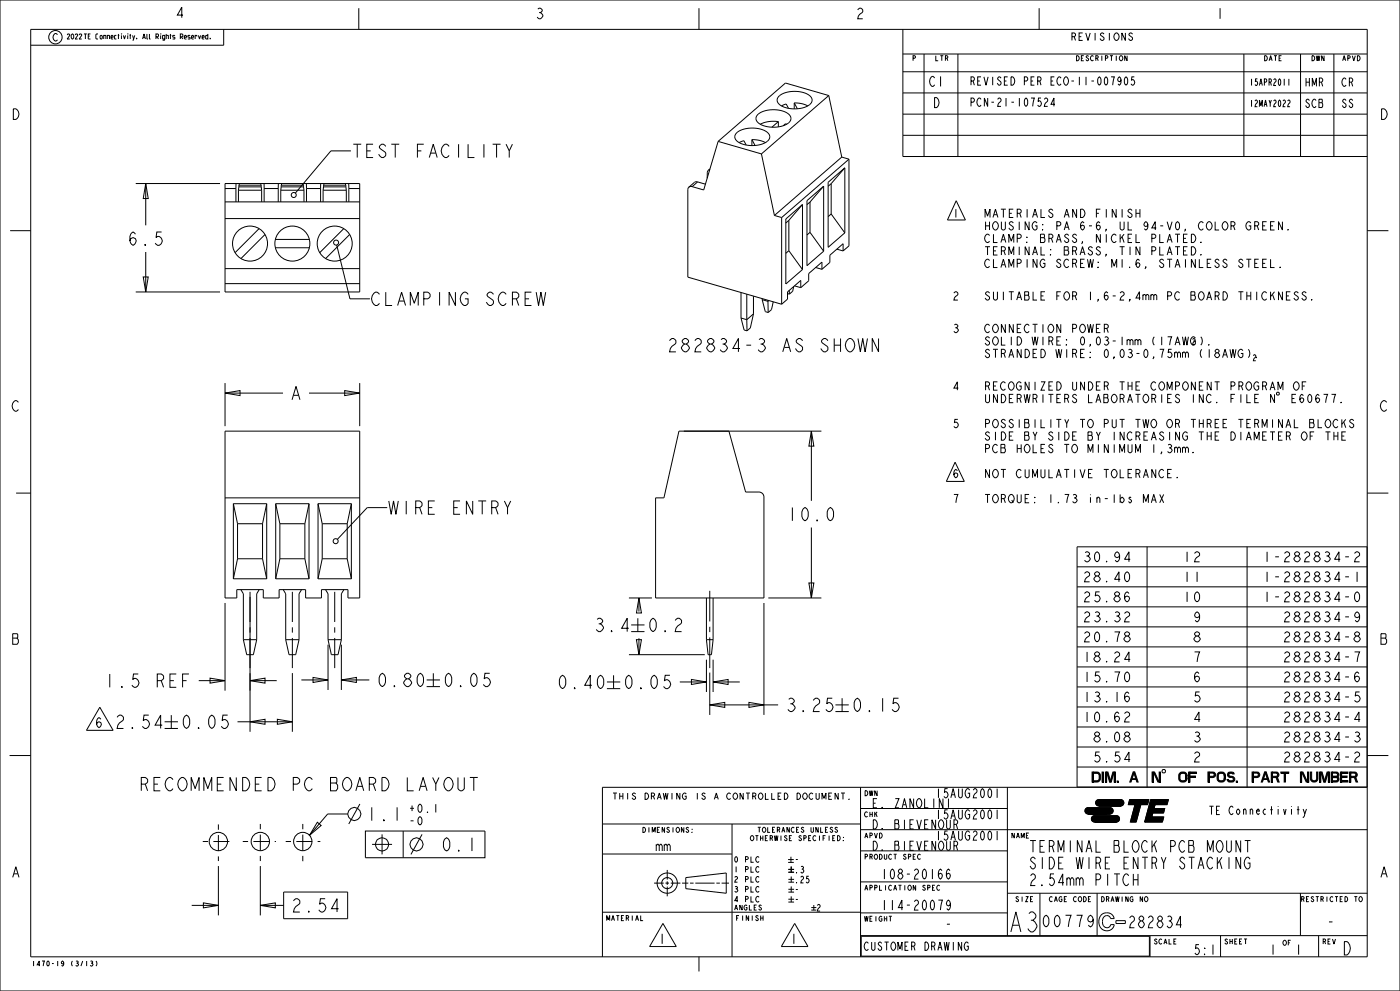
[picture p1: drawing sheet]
<svg xmlns="http://www.w3.org/2000/svg" width="420mm" height="297mm" viewBox="0 0 420 297" stroke-linecap="round" stroke-linejoin="round" font-family="sans-serif">
<defs><g id="words">
<text font-size="7.8" x="302.4" y="279.3">A3</text>
<g font-size="5.2">
<text x="105.3" y="47.2">TEST FACILITY</text>
<text x="38" y="73.5">6.5</text>
<text x="111" y="91.6">CLAMPING SCREW</text>
<text x="205.7" y="105.5">282834-3 AS SHOWN</text>
<text x="86.9" y="119.8">A</text>
<text x="116.2" y="154.1">WIRE ENTRY</text>
<text x="235.8" y="156.1">10.0</text>
<text x="177.9" y="189.3">3.4</text>
<text x="194" y="189.3">0.2</text>
<text x="31" y="206">1.5</text>
<text x="45.5" y="206">REF</text>
<text x="112.8" y="205.8">0.80</text>
<text x="132.7" y="205.8">0.05</text>
<text x="166.9" y="206.4">0.40</text>
<text x="186.7" y="206.4">0.05</text>
<text x="235.4" y="213.3">3.25</text>
<text x="255.3" y="213.3">0.15</text>
<text x="34.2" y="218.3">2.54</text>
<text x="54" y="218.3">0.05</text>
<text x="50.6" y="237">RECOMMENDED PC BOARD LAYOUT</text>
<text x="87.1" y="273.3">2.54</text>
<text x="402.5" y="286.2">D</text>
</g>
<g font-size="4.6">
<text x="308.5" y="255.4">TERMINAL BLOCK PCB MOUNT</text>
<text x="308.5" y="260.4">SIDE WIRE ENTRY STACKING</text>
<text x="308.5" y="265.4">2.54mm PITCH</text>
<text x="312.2" y="277.8">00779</text>
<text x="338.2" y="278">282834</text>
<text x="397.8" y="278">-</text>
</g>
<g font-size="4.1">
<text x="52.5" y="5.3">4</text>
<text x="160.4" y="5.6">3</text>
<text x="256.6" y="5.6">2</text>
<text x="364.5" y="5.6">1</text>
<text x="3.2" y="35.8">D</text>
<text x="413.7" y="35.8">D</text>
<text x="3.2" y="123.2">C</text>
<text x="413.7" y="123.2">C</text>
<text x="3.2" y="193.1">B</text>
<text x="413.7" y="193.1">B</text>
<text x="3.2" y="262.9">A</text>
<text x="413.7" y="262.9">A</text>
</g>
<g font-size="3.9">
<text x="278.6" y="25.9">C1</text>
<text x="279.8" y="32.2">D</text>
<text x="324.6" y="168.4">30.94</text>
<text x="378.1" y="168.4">1-282834-2</text>
<text x="324.6" y="174.4">28.40</text>
<text x="378.1" y="174.4">1-282834-1</text>
<text x="324.6" y="180.4">25.86</text>
<text x="378.1" y="180.4">1-282834-0</text>
<text x="324.6" y="186.4">23.32</text>
<text x="383" y="186.4">282834-9</text>
<text x="324.6" y="192.4">20.78</text>
<text x="383" y="192.4">282834-8</text>
<text x="324.6" y="198.4">18.24</text>
<text x="383" y="198.4">282834-7</text>
<text x="324.6" y="204.4">15.70</text>
<text x="383" y="204.4">282834-6</text>
<text x="324.6" y="210.4">13.16</text>
<text x="383" y="210.4">282834-5</text>
<text x="28.3" y="218.1">6</text>
<text x="324.6" y="216.4">10.62</text>
<text x="383" y="216.4">282834-4</text>
<text x="327.1" y="222.4">8.08</text>
<text x="383" y="222.4">282834-3</text>
<text x="327.1" y="228.4">5.54</text>
<text x="383" y="228.4">282834-2</text>
<text x="327.1" y="234.4">DIM. A</text>
<text x="375.6" y="234.4">PART NUMBER</text>
<text x="196.6" y="255">mm</text>
<text x="264.1" y="263.5">108-20166</text>
<text x="264.1" y="272.8">114-20079</text>
<text x="283.3" y="278.5">-</text>
<text x="197.2" y="282.9">1</text>
<text x="236.7" y="282.9">1</text>
<text x="357.9" y="286.1">5:1</text>
<text x="380.7" y="286.1">1</text>
<text x="388.4" y="286.1">1</text>
</g>
<g font-size="3.6">
<text x="280.4" y="239.1">15AUG2001</text>
<text x="261.4" y="242.1">E. ZANOLINI</text>
<text x="280.4" y="245.5">15AUG2001</text>
<text x="261.4" y="248.4">D. BIEVENOUR</text>
<text x="280.4" y="251.8">15AUG2001</text>
<text x="261.4" y="254.9">D. BIEVENOUR</text>
</g>
<g font-size="3.3">
<text x="290.8" y="25.5">REVISED PER ECO-11-007905</text>
<text x="391.3" y="25.9">HMR</text>
<text x="402.3" y="25.9">CR</text>
<text x="290.8" y="31.9">PCN-21-107524</text>
<text x="391.3" y="32.2">SCB</text>
<text x="402.3" y="32.2">SS</text>
<text x="285.6" y="65.2">1</text>
<text x="293.4" y="65.2">MATERIALS AND FINISH</text>
<text x="293.4" y="68.9">HOUSING: PA 6-6, UL 94-V0, COLOR GREEN.</text>
<text x="293.4" y="72.7">CLAMP: BRASS, NICKEL PLATED.</text>
<text x="293.4" y="76.4">TERMINAL: BRASS, TIN PLATED.</text>
<text x="293.4" y="80.2">CLAMPING SCREW: M1.6, STAINLESS STEEL.</text>
<text x="285.6" y="89.9">2</text>
<text x="293.4" y="89.9">SUITABLE FOR 1,6-2,4mm PC BOARD THICKNESS.</text>
<text x="285.6" y="99.7">3</text>
<text x="293.4" y="99.7">CONNECTION POWER</text>
<text x="293.4" y="103.4">SOLID WIRE: 0,03-1mm (17AWG).</text>
<text x="293.4" y="107.2">STRANDED WIRE: 0,03-0,75mm (18AWG).</text>
<text x="285.6" y="116.9">4</text>
<text x="293.4" y="116.9">RECOGNIZED UNDER THE COMPONENT PROGRAM OF</text>
<text x="285.6" y="128.2">5</text>
<text x="293.4" y="128.2">POSSIBILITY TO PUT TWO OR THREE TERMINAL BLOCKS</text>
<text x="293.4" y="131.9">SIDE BY SIDE BY INCREASING THE DIAMETER OF THE</text>
<text x="293.4" y="135.7">PCB HOLES TO MINIMUM 1,3mm.</text>
<text x="285.6" y="143.2">6</text>
<text x="293.4" y="143.2">NOT CUMULATIVE TOLERANCE.</text>
<text x="285.6" y="150.7">7</text>
<text x="293.4" y="150.7">TORQUE: 1.73 in-lbs MAX</text>
<text x="122.4" y="243.5">+0.1</text>
<text x="362.4" y="244.1">TE Connectivity</text>
<text x="122.4" y="247.2">-0</text>
<text x="259" y="284.8">CUSTOMER DRAWING</text>
</g>
<g font-size="2.9">
<text x="15.6" y="12.3">C</text>
<text x="321.1" y="12.1">REVISIONS</text>
</g>
<g font-size="2.6">
<text x="374.8" y="25.6">15APR2011</text>
<text x="374.8" y="32">12MAY2022</text>
<text x="238.2" y="258.6">-</text>
<text x="238.2" y="261.6">.3</text>
<text x="238.2" y="264.6">.25</text>
<text x="238.2" y="267.6">-</text>
<text x="238.2" y="270.6">-</text>
<text x="244.8" y="273.1">2</text>
</g>
<text font-size="2.5" x="190" y="239.6">THIS DRAWING IS A CONTROLLED DOCUMENT.</text>
<g font-size="2.3">
<text x="357.4" y="103.3">2</text>
<text x="375.7" y="108.1">2</text>
</g>
<g font-size="2.2">
<text x="220" y="258.4">0 PLC</text>
<text x="220" y="261.4">1 PLC</text>
<text x="220" y="264.4">2 PLC</text>
<text x="220" y="267.4">3 PLC</text>
<text x="220" y="270.3">4 PLC</text>
</g>
<g font-size="2">
<text x="19.9" y="11.7">2022TE Connectivity. All Rights Reserved.</text>
<text x="273.6" y="18.2">P</text>
<text x="280.4" y="18.2">LTR</text>
<text x="322.6" y="18.2">DESCRIPTION</text>
<text x="379" y="18.2">DATE</text>
<text x="393.2" y="18.2">DWN</text>
<text x="402.5" y="18.2">APVD</text>
<text x="259.2" y="238.5">DWN</text>
<text x="259.2" y="244.8">CHK</text>
<text x="192.5" y="249.5">DIMENSIONS:</text>
<text x="224.9" y="252">OTHERWISE SPECIFIED:</text>
<text x="227.1" y="249.5">TOLERANCES UNLESS</text>
<text x="259.2" y="251.2">APVD</text>
<text x="303.2" y="251.2">NAME</text>
<text x="259.2" y="257.5">PRODUCT SPEC</text>
<text x="259.2" y="266.8">APPLICATION SPEC</text>
<text x="181.7" y="275.9">MATERIAL</text>
<text x="220.1" y="272.8">ANGLES</text>
<text x="220.6" y="275.9">FINISH</text>
<text x="304.5" y="270.2">SIZE</text>
<text x="314.6" y="270.2">CAGE CODE</text>
<text x="330.1" y="270.2">DRAWING NO</text>
<text x="390.1" y="270.2">RESTRICTED TO</text>
<text x="259.2" y="276.1">WEIGHT</text>
<text x="346" y="282.9">SCALE</text>
<text x="367.2" y="282.9">SHEET</text>
<text x="384.7" y="283.3">OF</text>
<text x="396.6" y="282.9">REV</text>
<text x="9.3" y="289.5">1470-19 (3/13)</text>
</g>
</g></defs>
<g fill="none" stroke="#000" stroke-width=".3">
<path d="M0 0h420v297h-420zM9.2 8.8h401v278h-401zM67.1 8.8v4.8h-57.9M107.6 2.5v6.3M209.7 2.5v6.3M270.9 8.8v38.1h139.3M270.9 16.2h139.3M277.2 16.2v30.7M287.4 16.2v30.7M311.7 2.5v6.3M336.1 16.8l.1-.1a.77 .77 0 0 1 .7 .8 .77 .77 0 0 1-.7 .7l-.4-.7zM337.6 9.9v2.2l-1.1-2.2v2.2"/>
<path d="M338.1 16.7v1.5l-.7-1.5v1.5M339.8 10.2l-.4-.3-.7 .3 .1 .4 1 .8-.2 .5-.5 .2-.5-.5M373.2 16.2v30.7M384.4 16.7h-.7v1.5h.7M390.2 16.2v30.7M400.2 16.2v30.7M407.2 16.7a.76 .76 0 0 1 .8 .8 .76 .76 0 0 1-.8 .7zM233.5 36.4h-2.8l-2.6 .8M233.5 36.4l-1.9 1.7M233.5 36.4v1.6M234.5 31.7l1.4-.5 .6 1.3M236 37.2l-.3-.1-.7 .6"/>
<path d="M238.3 30.8l2.1 .3 1.9 .6M238.3 30.8v1.8M238.3 30.8l.9 1.8M248.6 28.6l-13-3.7-20.2 17.5M248.6 28.6l-20.2 17.5M248.6 28.6l3.9 18.5M270.9 34.2h139.3M270.9 21.5h139.3M270.9 27.9h139.3M313.3 29.8l.6-.4 .4 .4-.1 .6a1.68 1.68 0 0 0-.9 1.5h1M316.4 31.3h-1.1l.9-1.9v2.5M333.3 23h1l-.5 2.5"/>
<path d="M336.3 23.9l-.1 .4-.4 .2-.4-.2a.98 .98 0 0 1 .4-1.3 1.69 1.69 0 0 1 0 2.5l-.4-.4M337.6 23.2l.2-.2a1.69 1.69 0 0 1 0 2.5 1.77 1.77 0 0 1-.2-2.3zM340.3 23h-.7l-.2 1.1 .3-.2a.84 .84 0 0 1 .7 .8 .84 .84 0 0 1-.7 .8l-.4-.4M386.3 30.3l.3-.3 .4 .3-.7 1.7h.7M386.7 23.6v2M67.5 55h40.4v32.5h-40.4zM67.5 56.5h3.3M70.8 56.5v4M70.8 55v1.5M71.5 57v3.5M71.5 57h7M71.7 56l-.2 1"/>
<path d="M71.7 56v-.5h6.7v.5M71.7 56h6.7M71.8 55v.5M78.3 55v.5M78.4 56l.1 1M78.5 57v3.5M79.2 55v1.5M79.2 56.5v4M79.2 56.5h4.3M83.5 56.5v4M83.5 55v1.5M84.2 57v3.5"/>
<path d="M84.2 57h7M84.4 56l-.2 1M84.4 56v-.5h6.7v.5M84.4 56h6.7M84.5 55v.5M91 55v.5M91.1 56l.1 1M91.2 57v3.5M91.9 55v1.5M91.9 56.5v4M91.9 56.5h4.3M96.2 56.5v4"/>
<path d="M96.2 55v1.5M96.9 57v3.5M96.9 57h7M97.1 56l-.2 1M97.1 56v-.5h6.7v.5M97.1 56h6.7M97.2 55v.5M103.7 55v.5M103.8 56l.1 1M103.9 57v3.5M104.6 55v1.5M104.6 56.5h3.3"/>
<path d="M104.6 56.5v4M206.7 56.1l-.4 .8v26.2l28.2 8.1M207.6 55.9l-.9 .2M209.3 54.5l-.9 .1-1.7 1.5M209.3 54.5l-1.7 1.4M209.3 54.5l2.3 .7M212.5 51l-.3 .6v1.8M212.9 50.8l-.4 .2M213 50.6l-.5 .4M215.4 42.4l-4.3 14.5-3.5-1M215.4 42.4l13 3.7M221.8 42.7l1.4-.5 .6 1.3"/>
<path d="M225.6 41.8l2.1 .3 1.9 .6M225.6 41.8v1.8M225.6 41.8l.9 1.8M228.4 46.1l3.9 18.5M247.1 55.8l-5 4.3v19.5l5-4.3M247.1 55.8l-4.1 4.7M247.1 55.8v19.5M249.4 55l-1 .8M249.4 55v9.1M252.5 47.1l-20.2 17.5M252.5 47.1l2.2 .6M253.4 50.3l-5 4.3v19.5l5-4.3"/>
<path d="M253.4 50.3l-4 4.7M253.4 50.3v19.5M254.7 47.7l-20.2 17.5M254.7 47.7v26l-1.8 1.5M270.9 40.6h139.3M3 69.1h6.2M67.5 65.5h40.4M67.5 60.5h40.4M77.7 68.5l-7.2 7.2M79.5 70.3l-7.2 7.2M82.6 74.3h10.2M82.6 71.8h10.2"/>
<path d="M103.1 68.5l-7.2 7.2M104.9 70.3l-7.2 7.2M232.3 64.6l2.2 .6M234.5 65.2v26M236.7 75.1l4 5.7M236.7 66v9.1M236.7 66l-1 .8M236.7 75.1l-1 .8M240.7 61.3l-5 4.3v19.5l5-4.3M240.7 61.3l-4 4.7M240.7 61.3v19.5M243 69.6l4.1 5.7"/>
<path d="M243 60.5l-.9 .8M243 60.5v9.1M243 69.6l-.9 .8M249.4 64.1l-1 .8M249.4 64.1l4 5.7M251.1 74.7l1.8 .5M252.9 75.2v-2.2l-3.9 3.5v2.2l-2.4 2M410.2 69.1h6.3M67.5 85h40.4M67.5 80.5h40.4M222.3 95.3l.9 3.6 .9 .2M222.3 95.3l1.7 .5"/>
<path d="M222.3 87.7v7.6M224 95.8l.1 3.3M224 88.2v7.6M226 88.7v5.4M226 94.1l-.9 4.2-1 .8M226 94.1l-2 1.7M228.7 89.8l.9 3.6 .9 .3M228.7 89.8l1.7 .5M228.7 89.5v.3M230.4 90.3l.1 3.4M230.4 90v.3M230.7 90.1l-.3 .2"/>
<path d="M232 90.5l-.5 2.3-1 .9M236.3 88l.5 .2M236.8 87v1.2M238.1 85.9l-.3 1.4-1 .9M238.4 85.7l1.8 .5M240.2 86.2v-2.2l-3.9 3.5v2.2l-1.8 1.5M244.7 80.2l1.9 .5M246.6 80.7v-2.2l-4 3.5v2.2l-2.4 2M67.5 129.2h40.4v50h-3.5v-2.5h-8v2.5h-4.7v-2.5h-8v2.5h-4.7v-2.5h-8v2.5h-3.5zM203.7 129.2h15l5 18.3h4a1.5 1.5 0 0 1 1.5 1.5v30.2h-32.5v-30h2.5zM4.8 147.8h4.4M67.5 149.2h40.4"/>
<path d="M70 151v22.5M70 151l1.3 6M70 151h10M71.3 157v10.5M71.3 157h7.5M78.8 157v10.5M80 151v22.5M80 151l-1.2 6M82.7 151v22.5M82.7 151l1.3 6M82.7 151h10M84 157v10.5"/>
<path d="M84 157h7.5M91.5 157v10.5M92.7 151l-1.2 6M92.7 151v22.5M95.4 151v22.5M95.4 151l1.3 6M95.4 151h10M96.7 157h7.5M96.7 157v10.5M104.2 157v10.5M105.4 151l-1.2 6M105.4 151v22.5"/>
<path d="M410.2 147.8h6.3M70 173.5h10M71.3 167.5l-1.3 6M71.3 167.5h7.5M72.3 176.7l.7 1.3v13.7M75 177.4v9M77.8 176.7l-.8 1.3v13.7M78.8 167.5l1.2 6M82.7 173.5h10M84 167.5l-1.3 6M84 167.5h7.5M85 176.7l.7 1.3v13.7"/>
<path d="M87.7 177.4v9M90.5 176.7l-.8 1.3v13.7M91.5 167.5l1.2 6M95.4 173.5h10M96.7 167.5h7.5M96.7 167.5l-1.3 6M97.7 176.7l.7 1.3v13.7M100.4 177.4v9M103.2 176.7l-.8 1.3v13.7M104.2 167.5l1.2 6M188.7 179.2h6.9M191.7 179.2l.7 4.5h-1.5z"/>
<path d="M191.7 179.2v4.1M211.9 179.2v12.5M212.9 177.1v9.1M213.9 179.2v12.5M323.1 163.9h87v72h-87zM323.1 175.9h87M323.1 169.9h87M344.1 163.9v72M374.1 163.9v72M73 191.7l1 4.5h2l1-4.5M73 191.7h4M75 188v1.6"/>
<path d="M75 191.2v9M85.7 191.7l1 4.5h2l1-4.5M85.7 191.7h4M87.7 188v1.6M87.7 191.2v9M98.4 191.7l1 4.5h2l1-4.5M98.4 191.7h4M100.4 188v1.6M100.4 191.2v9M188.6 188.3h-2.1l1.7-3v4M188.7 196.2h22.7M189.3 187.3h4"/>
<path d="M189.3 189.3h4M190.9 191.7h1.5l-.7 4.5zM191.3 185.3v4M191.7 191.3v4.9M211.9 191.7l.5 4.5h1l.5-4.5M211.9 191.7h2M212.9 187.8v1.6M212.9 191v9.2M229.2 180.7v33.6M323.1 199.9h87M323.1 193.9h87M323.1 187.9h87"/>
<path d="M323.1 181.9h87M212.9 211.3l4.5-.8v1.5zM212.9 211.3h20.5M212.9 201.6v12.7M224.7 210.5l4.5 .8-4.5 .7zM249.7 209.3h-1.4l-.3 1.6 .5-.3a1.34 1.34 0 0 1 1.4 1.3 1.34 1.34 0 0 1-1.4 1.4l-.7-.7M250.6 211.3h4M250.6 213.3h4M252.6 209.3v4M269.5 209.3h-1.4l-.2 1.6 .5-.3a1.34 1.34 0 0 1 1.4 1.3 1.34 1.34 0 0 1-1.4 1.4l-.8-.7M323.1 217.9h87M323.1 211.9h87"/>
<path d="M323.1 205.9h87M2.9 226.4h6.3M183.9 237.7h1.2M184.5 237.7v1.9M185.9 237.7v1.9M185.9 238.6h1M186.9 237.7v1.9M188.3 237.7v1.9M249.6 237.7h-1v1.9h1M251.5 237.7v1.9l-1-1.9v1.9M252.3 237.7h1.2M252.9 237.7v1.9"/>
<path d="M254.7 239.4l.1 .2zM258.2 236v50.8M282.9 239.3v2.8l-1.1-2.8v2.8M284.5 239.3v2.8M299.1 236.4v2.7M302.2 236v44.4M323.1 229.9h87M323.1 223.9h87M329 239.9l.6-.3h6.6a.95 .95 0 0 1 .9 .9 .95 .95 0 0 1-.8 1h-6.7a.95 .95 0 0 1-.8-.5 .95 .95 0 0 1 .2-1.1zM338.9 239.6h5.8l-.4 1.5h-2.1l-1.4 5.3h-1.7l1.4-5.3h-2zM345.2 239.6h5.3l-.4 1.5h-3.6l-3.1 5.3zM345.2 239.6h5.3l-.4 1.5h-3.6l-.3 1.2h3.2l-.3 1.3h-3.3l-.3 1.3h3.6l-.4 1.5h-5.3z"/>
<path d="M410.2 236h-229.5v50.8M410.2 226.4h6.3M180.7 255.9h38.9M180.8 246.9h77.4M206.6 248.2l-.3-.2-.4 .2 .7 .8-.1 .3-.4 .2-.3-.4M207.6 248.5l.1 .1zM207.6 249.3l.1 .2zM219.6 246.9v39.9M227.7 257l-.3-.3a.87 .87 0 0 0-.7 .9 .87 .87 0 0 0 .7 .8l.3-.3M227.7 260l-.3-.3a.87 .87 0 0 0-.7 .9 .87 .87 0 0 0 .7 .8l.3-.3M236.4 257.6h1.7M236.4 258.5h1.7"/>
<path d="M237.3 256.8v1.7M237.4 259.7v1.7M247.6 248.7h.5M248.4 247.9h-.8v1.6h.8M249.8 248.2l-.3-.3-.4 .3 .7 .7-.1 .4-.4 .2-.3-.4M249.8 251.2h.5M250.5 250.4h-.7v1.6h.7M251.2 248.2l-.2-.3-.5 .3 .7 .7v.4l-.4 .2-.4-.4M251.3 250.4a.76 .76 0 0 1 .8 .8 .76 .76 0 0 1-.8 .8zM253 250.9l.1 .2zM253 251.8l.1 .2zM258.2 242.3h44"/>
<path d="M258.2 255h44M258.2 248.7h152M263.9 249.7a.76 .76 0 0 1 .8 .7 .76 .76 0 0 1-.8 .8zM274 256.8h.4M274.7 256h-.7v1.5h.7M276.1 256.3l-.2-.3a.77 .77 0 0 0-.7 .8 .77 .77 0 0 0 .7 .7l.2-.2M284 252.1v2.3l.4 .5h.3l.4-.5v-2.3M284 245.7v2.3l.4 .4h.3l.4-.4v-2.3M286.2 253.5h.7l.4-.5v-.4l-.4-.5h-.7v2.8M286.2 247.1h.7l.4-.5v-.4l-.4-.5h-.7v2.7M286.9 253.5l.4 1.4M286.9 247.1l.4 1.3"/>
<path d="M299.1 242.7v2.8M299.1 249.1v2.7M308.6 249.7h-.7v1.5h.7M325.8 242.3l.6-.3h6.6a.95 .95 0 0 1 .9 .9 .95 .95 0 0 1-.8 1l-6.7 .1a.95 .95 0 0 1-.8-.6 .95 .95 0 0 1 .2-1.1zM326.4 244l6.7-.1zM327.7 244.7l.7-.2h6.5a.95 .95 0 0 1 1 .8 .95 .95 0 0 1-.9 1l-6.6 .1a.95 .95 0 0 1-.9-.6 .95 .95 0 0 1 .2-1.1zM328.4 246.4l6.6-.1zM329.6 241.5h6.7zM333.1 243.9l-6.7 .1a.95 .95 0 0 1-.9-1 .95 .95 0 0 1 .9-1h6.6a.95 .95 0 0 1 .9 1 .95 .95 0 0 1-.9 1M335 246.4h-6.6a.95 .95 0 0 1-1-1 .95 .95 0 0 1 1-.9h6.5a.95 .95 0 0 1 1 .9 .95 .95 0 0 1-1 1M336.3 241.5h-6.7a.95 .95 0 0 1-.9-.9 .95 .95 0 0 1 .9-1h6.6a.95 .95 0 0 1 .9 1 .95 .95 0 0 1-.9 .9M345.8 243.6l-.3 1.3h3.6l-.4 1.5h-5.3z"/>
<path d="M346.5 241.1l-.3 1.2h3.2l-.3 1.3h-3.3l-2.4 2.8zM365.2 256.9v3.5M365.4 252.2l.3-.3a1.86 1.86 0 0 1 1.2 1.8 1.86 1.86 0 0 1-1.2 1.7l-.3-.3a2.29 2.29 0 0 1 0-2.9zM365.9 258.1l.7 2.3M366.6 256.9l-1.4 2M368 251.9v2.9l.5 .6h.4l.5-.6v-2.9M368.7 256.9v3.5M372.2 251.9v3.5l-1.4-3.5v3.5M372.2 256.9v3.5l-1.4-3.5v3.5M373.4 251.9h1.8M374.3 251.9v3.5M375 257.5l-.5-.6a1.86 1.86 0 0 0-1.3 1.8 1.86 1.86 0 0 0 1.3 1.7l.5-.6v-1.1h-.7"/>
<path d="M389.1 242.7h.7M389.4 241.6v2.5M390.9 242.5l.5 1.4-.1 .6-.2 .5h-.3M391.9 242.5l-.5 1.4M180.7 273.4h77.5M192.2 274.4v1.5h.7M196.2 264.7h2.9M199.6 264.7h1.1M200.2 260.7v2.9M200.2 264.1v1.1M200.2 265.7v2.9M201.2 264.7h2.9"/>
<path d="M204.6 264.7h1.9M205.7 263l12.2-1.4v6.1l-12.2-1.4zM207 264.7h1.1M208.6 264.7h5.8M214.9 264.7h1.1M216.5 264.7h2.2M227.7 263l-.3-.3a.87 .87 0 0 0-.7 .8 .87 .87 0 0 0 .7 .9l.3-.3M227.7 265.9l-.3-.2a.87 .87 0 0 0-.7 .8 .87 .87 0 0 0 .7 .9l.3-.3M227.7 268.9l-.3-.3a.87 .87 0 0 0-.7 .9 .87 .87 0 0 0 .7 .8l.3-.2M228.2 275.2h.7M228.4 271.5l-.2-.3-.5 .3 .7 .7-.1 .4-.3 .2-.4-.4M228.9 274.4v1.5"/>
<path d="M236.5 260.6h1.7M236.5 269.5h1.7M236.5 266.5h1.7M236.5 263.5h1.7M236.5 261.4h1.7M236.5 270.3h1.7M236.5 267.4h1.7M236.5 264.4h1.7M237.4 262.7v1.7M237.4 265.7v1.7M237.4 268.6v1.7M243.4 272h1.5"/>
<path d="M243.4 272.8h1.5M258.2 273.6h44M258.2 264.3h44M266.7 274.6h.9M267.1 274.6v1.5M278.3 266.1l.6-.2v-.5l-.6-.1v1.5M279.7 266.1h.5M280.5 265.3h-.8v1.5h.8M281.9 265.6l-.3-.3a.77 .77 0 0 0-.6 .8 .77 .77 0 0 0 .6 .7l.3-.2M285 261l-.5-.5a2.03 2.03 0 0 0 0 3 .99 .99 0 0 0 0-1.8l-.4 .3-.2 .5M285.1 270.8l-.1 .5-.5 .2-.4-.2a1.17 1.17 0 0 1 .4-1.5 2.03 2.03 0 0 1 0 3l-.4-.5M302.2 267.7h108"/>
<path d="M309.9 268.7h-.7v1.5h.7M312 267.7v12.7M325.1 268.7a.76 .76 0 0 1 .8 .8 .76 .76 0 0 1-.8 .7zM326.5 269.5h.5M327.2 268.7h-.7v1.5h.7M328 275.5l-.2 .6-.7 .2-.6-.2a1.27 1.27 0 0 1 .6-1.8l.4 .3a2.21 2.21 0 0 1-.4 3.2l-.6-.6M329.1 267.7v12.7M330.4 274.2l.8-.5 1.1-.1 .9 .2 .7 .7 .4 .8h-1.1l-.5-.7-.7-.2-.9 .4-.3 .9 .1 1.4 .8 .9 .9-.1 .6-.8h1.1l-.3 .8-.6 .7-.8 .3h-.9l-.9-.3-.7-.6-.4-.9v-1.1l.2-1zM337.6 275.9h-2.8v.9h2.8M338.6 262.5l-.5-.6a1.86 1.86 0 0 0-1.3 1.8 1.86 1.86 0 0 0 1.3 1.7l.5-.6M340 261.9v3.5M340 263.7h1.4"/>
<path d="M341.4 261.9v3.5M342.8 268.7v1.5l-.8-1.5v1.5M343.6 268.8l.2-.1a.77 .77 0 0 1 .6 .8 .77 .77 0 0 1-.6 .7l-.5-.7zM354.5 277.2h-1.6l1.2-2.7v3.5M406.3 268.7h.9M406.7 268.7v1.5M407.9 268.8l.2-.1a.77 .77 0 0 1 .6 .8 .77 .77 0 0 1-.6 .7l-.5-.7zM27.2 288.1l.3-.1 .3 .3-.3 .3a.42 .42 0 0 1 .3 .7 .42 .42 0 0 1-.7 0M27.4 288.6h.1M28.8 288l.3 .9-.3 .6M209.7 286.8v4.3M258.2 280.4h152"/>
<path d="M258.4 280.6h86.4v6h-86.4zM288.5 282.3v2.5l-1-2.5v2.5M290.5 282.7l-.4-.4a1.33 1.33 0 0 0-.9 1.3 1.33 1.33 0 0 0 .9 1.2l.4-.4v-.8h-.5M345 280.4v6.4M352.2 282.2h.4M352.9 281.4h-.7v1.5h.7M366.2 280.4v6.4M373.2 281.4h.9M373.7 281.4v1.5M395.6 280.4v6.4"/>
<circle cx="16.6" cy="11.2" r="2.01"/>
<circle cx="200.2" cy="264.7" r="3"/>
<circle cx="200.2" cy="264.7" r="1.66"/>
</g>
<path d="M329 239.9l.6-.3h6.6a.95 .95 0 0 1 .9 .9 .95 .95 0 0 1-.8 1h-6.7a.95 .95 0 0 1-.8-.5 .95 .95 0 0 1 .2-1.1zM345.2 239.6h5.3l-.4 1.5h-3.6l-3.1 5.3zM325.8 242.3l.6-.3h6.6a.95 .95 0 0 1 .9 .9 .95 .95 0 0 1-.8 1l-6.7 .1a.95 .95 0 0 1-.8-.6 .95 .95 0 0 1 .2-1.1zM327.7 244.7l.7-.2h6.5a.95 .95 0 0 1 1 .8 .95 .95 0 0 1-.9 1l-6.6 .1a.95 .95 0 0 1-.9-.6 .95 .95 0 0 1 .2-1.1zM338.9 239.6h5.8l-.4 1.5h-2.1l-1.4 5.3h-1.7l1.4-5.3h-2zM345.8 243.6l-.3 1.3h3.6l-.4 1.5h-5.3zM346.5 241.1l-.3 1.2h3.2l-.3 1.3h-3.3l-2.4 2.8z" fill="#000"/>
<!-- layer: DIM_DRIVEN -->
<g fill="none" stroke="#000" stroke-width=".3">
<path d="M40.7 55h25.3M43.7 55l.8 4.5h-1.5zM43.7 55v12.5M43.7 75.5v12M48.5 69.5h-1.5l-.2 1.7 .5-.3a1.34 1.34 0 0 1 1.4 1.3 1.34 1.34 0 0 1-1.4 1.3l-.7-.6M40.7 87.5h25.3M43 83h1.5l-.8 4.5zM67.5 117.8l4.5-.7v1.5zM67.5 114.8v12.9M67.5 117.8h17.4M92.7 117.8h15.2M103.4 117.1l4.5 .7-4.5 .8z"/>
<path d="M107.9 114.8v12.9M205.2 129.2h41.2M243.4 129.2l.8 4.5h-1.5zM243.4 129.2v20.9M243.4 158.1v21.1M248.6 152.4l.5-.3 .5 .3a2.53 2.53 0 0 1-.5 3.7l-.5-.3a2.77 2.77 0 0 1 0-3.4zM230.5 179.2h15.9M242.7 174.7h1.5l-.8 4.5zM98.4 193.2v13.6M102.4 193.2v13.6M211.9 197.7v9.7M213.9 197.7v9.7"/>
<path d="M48.7 217.3h-2.2l1.7-3v4M49.4 216.3h4M49.4 218.3h4M51.4 214.3v4M68.3 214.3h-1.4l-.3 1.7 .5-.3a1.34 1.34 0 0 1 1.4 1.3 1.34 1.34 0 0 1-1.4 1.3l-.7-.6M71.2 216.3h16.5M75 216.3l4.5-.7v1.5zM75 201.7v17.6M83.2 215.6l4.5 .7-4.5 .8zM87.7 201.7v17.6M90.4 203.8h8M93.9 203l4.5 .8-4.5 .7z"/>
<path d="M102.4 203.8l4.5-.8v1.5zM102.4 203.8h8.4M125.6 202.1l.5-.3 .5 .3a2.53 2.53 0 0 1-.5 3.7l-.5-.4a2.77 2.77 0 0 1 0-3.3zM128 203.8h4M128 205.8h4M130 201.8v4M146.9 201.8h-1.4l-.2 1.6 .4-.3a1.34 1.34 0 0 1 1.5 1.3 1.34 1.34 0 0 1-1.5 1.4l-.7-.7M179.7 202.7l.5-.3 .4 .3a2.53 2.53 0 0 1-.4 3.7l-.5-.4a2.77 2.77 0 0 1 0-3.3zM182.1 204.4h4M182.1 206.4h4M184.1 202.4v4M201 202.4h-1.4l-.3 1.6 .5-.3a1.34 1.34 0 0 1 1.4 1.3 1.34 1.34 0 0 1-1.4 1.4l-.7-.7"/>
<path d="M203.9 204.4h8M207.4 203.6l4.5 .8-4.5 .7zM213.9 204.4l4.5-.8v1.5zM213.9 204.4h8M65.5 259.6v14.7M78.1 259.6v14.7M57.5 271.3h8M61 270.6l4.5 .7-4.5 .8zM78.1 271.3l4.5-.7v1.5zM78.1 271.3h7M85.1 267.3h19.2v8h-19.2zM101.6 272.3h-2.2l1.7-3v4"/>
</g>
<!-- layer: DIM_PART_REF -->
<path d="M75 178.9v28.1M67.5 180.7v26.3M41.5 202h-1.4l-.3 1.7 .5-.4a1.34 1.34 0 0 1 1.4 1.4 1.34 1.34 0 0 1-1.4 1.3l-.7-.7M56.7 202h-1.9v4M59.6 204h7.9M63 203.2l4.5 .8-4.5 .7zM75 204l4.5-.8v1.5zM75 204h8" fill="none" stroke="#000" stroke-width=".3"/>
<!-- layer: DRAFT_ENTITY -->
<path d="M60.8 252.2h9M65.5 247.1v11M72.8 252.2h10M78.1 246.9v11.2M85.7 252.2h10.4M90.8 246.9v11.3" fill="none" stroke="#000" stroke-width=".3" stroke-dasharray="1.6 1.6 4.8 1.6" stroke-linecap="butt"/>
<g fill="none" stroke="#000" stroke-width=".3">
<path d="M286.9 60.2l2.7 5.7h-5.4zM286.5 138.5l2.8 5.8h-5.4zM390.1 267.7v12.7"/>
<circle cx="65.5" cy="252.2" r="2.75"/>
<circle cx="78.1" cy="252.2" r="2.75"/>
<circle cx="90.8" cy="252.2" r="2.75"/>
</g>
<!-- layer: DTM_AXIS -->
<g fill="none" stroke="#000" stroke-width=".3">
<path d="M221 39.9l1.5-1 2.3-.5 2.4 .1 2.2 .6a1.78 1.78 0 0 1 1.1 3l-1.6 1-2.2 .5-2.6-.1-2.1-.6a1.78 1.78 0 0 1-1.1-3zM227.3 34.4l1.5-1 2.4-.5 2.4 .1 2.1 .6a1.78 1.78 0 0 1 1.1 3l-1.6 1-2.2 .5-2.5-.1-2.2-.6a1.78 1.78 0 0 1-1-3zM233.7 28.9l1.5-1 2.3-.5 2.4 .1 2.2 .6a1.78 1.78 0 0 1 1.1 3l-1.6 1-2.2 .5-2.6-.1-2.1-.6a1.78 1.78 0 0 1-1.1-3z"/>
<circle cx="75" cy="73" r="5.3"/>
<circle cx="87.7" cy="73" r="5.3"/>
<circle cx="100.4" cy="73" r="5.3"/>
</g>
<!-- layer: NOTE -->
<g fill="#000">
<path d="M346 231.4h.4l1.3 3h-.3zM354 231.6a1.26 1.26 0 0 1 1.3-.3 1.26 1.26 0 0 1 .8 1.1h-.4a.91 .91 0 0 0-.8-.7 .91 .91 0 0 0-.9 .7v1a.91 .91 0 0 0 .9 .6 .91 .91 0 0 0 .8-.6h.4a1.27 1.27 0 0 1-1.2 1 1.27 1.27 0 0 1-1.3-1l.1-1.4zM355.7 232.4h.4v1h-.4zM357 231.4h1.9v.4h-1.9zM357 232.6h1.6v.4h-1.6zM362.7 231.4h1.2a.83 .83 0 0 1 .8 .8 .83 .83 0 0 1-.8 .8h-1.2v-.3h1.2l.3-.4-.3-.6h-1.2zM365.5 231.6a1.26 1.26 0 0 1 1.3-.3 1.26 1.26 0 0 1 .8 1.1h-.4a.91 .91 0 0 0-.8-.7 .91 .91 0 0 0-.9 .7v1a.91 .91 0 0 0 .9 .6 .91 .91 0 0 0 .8-.6h.4a1.27 1.27 0 0 1-1.2 1 1.27 1.27 0 0 1-1.3-1l.1-1.4zM367.2 232.4h.4v1h-.4zM369.1 232.7a1.01 1.01 0 0 1 1.3 1.2 1.27 1.27 0 0 1-2.3-.3h.5l.3 .4 1-.2v-.6l-.8-.2zM368.5 231.5l.6-.1a.87 .87 0 0 1 1.1 .6l-1.3-.2-.2 .5 .4 .4v.3l-.4-.1-.5-.6zM370.9 234.1h.3v.3h-.3zM402.5 231.4h1.9v.4h-1.9z"/>
<path d="M402.5 232.6h1.6v.4h-1.6zM402.5 234h1.9v.4h-1.9zM405.2 231.4h1.2a.83 .83 0 0 1 .8 .8 .83 .83 0 0 1-.8 .8h-1.2v-.3h1.2l.3-.4-.3-.6h-1.2zM406.2 232.8h.5l.5 1.6h-.4z"/>
</g>
<g fill="none" stroke="#000" stroke-width=".3">
<path d="M105.3 45.2h-6l-10.7 12.7M147.8 43.2h2.4M149 43.2v4M151.8 43.2l1 2v2M153.7 43.2l-.9 2M101 73.4l4 16.2h6M334.9 62.7v2.5l-1.2-2.5v2.5M336.6 62.7v2.5M339.6 63.1l-.4-.4a.62 .62 0 0 0-.8 .6l.5 .4a.73 .73 0 0 1 .7 .8 .73 .73 0 0 1-.7 .7l-.6-.6M340.8 62.7v2.5M340.8 63.9h1.2M342 62.7v2.5"/>
<path d="M347.9 70.2v2.5h1.2M347.9 73.9v2.5h1.2M350.1 72.7l.8-2.5 .7 2.5M350.1 76.4l.8-2.5 .7 2.5M350.4 71.9h.9M350.4 75.6h.9M352.5 73.9h1.5M353.3 70.2v2.5M353.3 73.9v2.5M355 71.4h.8M355 75.2h.8M356.2 70.2h-1.2v2.5h1.2"/>
<path d="M356.2 73.9h-1.2v2.5h1.2M357.4 70.2a1.25 1.25 0 0 1 1.4 1.2 1.25 1.25 0 0 1-1.4 1.3zM357.4 73.9a1.25 1.25 0 0 1 1.4 1.3 1.25 1.25 0 0 1-1.4 1.2zM360.2 72.5l.2 .2zM360.2 76.2l.2 .2zM368.1 78.1l-.4-.4a.62 .62 0 0 0-.8 .6l.5 .4a.73 .73 0 0 1 .7 .8 .73 .73 0 0 1-.7 .7l-.6-.6M369.3 67.7l1-.2v-.9l-1-.2v2.5M370 67.7l.5 1.2M372.9 78.1l-.5-.4a.62 .62 0 0 0-.7 .6l.4 .4a.73 .73 0 0 1 .8 .8 .73 .73 0 0 1-.8 .7l-.6-.6M373.9 77.7h1.5M374.6 77.7v2.5M375.2 66.9l-.4-.5a1.27 1.27 0 0 0-1.1 1.3 1.27 1.27 0 0 0 1.1 1.2l.4-.4v-.8h-.6"/>
<path d="M376.4 67.7l1.1-.2v-.9l-1.1-.2v2.5M376.4 78.9h.8M377.2 67.7l.4 1.2M377.6 77.7h-1.2v2.5h1.2M378.8 67.7h.7M378.8 78.9h.7M380 66.4h-1.2v2.5h1.2M380 77.7h-1.2v2.5h1.2M381.2 77.7v2.5h1.2M381.2 67.7h.7M382.4 66.4h-1.2v2.5h1.2M384 80l.1 .2z"/>
<path d="M384.7 66.4v2.5l-1.2-2.5v2.5M386.4 68.7l.1 .2zM157.5 89.6h1.2M159.4 87.6h-1.9v4h1.9M160.9 87.6l.7 4 .7-4 .7 4 .7-4M326.2 97.2l.5 2.5 .4-2.5 .5 2.5 .4-2.5M328.9 98.4h.8M330.1 97.2h-1.2v2.5h1.2M331.3 98.4l1-.2v-.8l-1-.2v2.5M332 98.4l.5 1.3M377 87.4v2.5M380 87.9l-.5-.5a1.27 1.27 0 0 0-1 1.3 1.27 1.27 0 0 0 1 1.2l.5-.4"/>
<path d="M381.2 87.4v2.5M381.8 88.3l.6 1.6M382.4 87.4l-1.2 1.5M384.7 87.4v2.5l-1.2-2.5v2.5M385.9 88.7h.8M387.1 87.4h-1.2v2.5h1.2M389.5 87.9l-.5-.5a.62 .62 0 0 0-.7 .7l.4 .4a.73 .73 0 0 1 .8 .7 .73 .73 0 0 1-.8 .7l-.6-.6M391.9 87.9l-.5-.5a.62 .62 0 0 0-.7 .7l.4 .4a.73 .73 0 0 1 .8 .7 .73 .73 0 0 1-.8 .7l-.6-.6M393.5 89.7l.1 .2zM200.9 102.1l.7-.6h.5l.7 .6a1.54 1.54 0 0 1-1.2 1.7l-.5 .7-.2 1h1.9M263.6 101.5v4l-1.9-4v4M295.7 118.2v2.1l.4 .4 .8-.4v-2.1"/>
<path d="M299.2 118.2v2.5l-1.2-2.5v2.5M300.4 118.2a1.25 1.25 0 0 1 1.4 1.2 1.25 1.25 0 0 1-1.4 1.3zM302.8 119.4h.7M304 118.2h-1.2v2.5h1.2M305.2 119.4l1-.2v-.8l-1-.2v2.5M305.9 119.4l.5 1.3M307.2 118.2l.5 2.5 .4-2.5 .5 2.5 .4-2.5M309.9 119.4l1.1-.2v-.8l-1.1-.2v2.5M310.7 119.4l.4 1.3M312.9 118.2v2.5M314.5 118.2h1.5M315.3 118.2v2.5"/>
<path d="M317 119.4h.8M318.2 118.2h-1.2v2.5h1.2M319.4 119.4l1.1-.2v-.8l-1.1-.2v2.5M320.2 119.4l.4 1.3M323 118.6l-.5-.4a.62 .62 0 0 0-.7 .6l.4 .4a.73 .73 0 0 1 .8 .8 .73 .73 0 0 1-.8 .7l-.6-.6M326.5 118.2v2.5h1.2M329.1 119.9h.9M331.1 118.2h1.1l.1 .2-.1 .8 .3 .4v.7l-.3 .4h-1.1zM331.1 119.2h1.1M333.8 118.4l.3-.2a1.27 1.27 0 0 1 1.1 1.2 1.27 1.27 0 0 1-1.1 1.3l-.3-.2a1.44 1.44 0 0 1 0-2.1zM336 119.4l1.1-.2v-.8l-1.1-.2v2.5M336.8 119.4l.4 1.3"/>
<path d="M338.6 119.9h.9M340.6 118.2h1.5M341.4 118.2v2.5M343.3 118.4l.3-.2a1.27 1.27 0 0 1 1.1 1.2 1.27 1.27 0 0 1-1.1 1.3l-.3-.2a1.44 1.44 0 0 1 0-2.1zM345.5 119.4l1.1-.2v-.8l-1.1-.2v2.5M346.3 119.4l.4 1.3M348.5 118.2v2.5M350.3 100.9h1.2l-.6 2.5M350.3 119.4h.7M351.5 118.2h-1.2v2.5h1.2M352.5 103.4l.8-2.5 .7 2.5M352.8 102.6h.9"/>
<path d="M353.9 118.6l-.5-.4a.62 .62 0 0 0-.7 .6l.4 .4a.73 .73 0 0 1 .8 .8 .73 .73 0 0 1-.8 .7l-.6-.6M354.7 100.9l.5 2.5 .4-2.5 .5 2.5 .4-2.5M358 118.2v2.5M358.6 101.4l-.4-.5a1.27 1.27 0 0 0-1.1 1.3 1.27 1.27 0 0 0 1.1 1.2l.4-.4v-.8h-.6M360.2 100.9a1.94 1.94 0 0 1 0 2.5M361 118.2v2.5l-1.2-2.5v2.5M362.6 103.2l.2 .2zM362.8 104.7v2.5M363.4 118.6l-.5-.4a1.27 1.27 0 0 0-1 1.2 1.27 1.27 0 0 0 1 1.3l.5-.4M365 105.7l-.5-.4a.62 .62 0 0 1 .8-.6l.4 .4-.4 .6M366.8 107.2l.7-2.5 .8 2.5M367.1 106.4h.9"/>
<path d="M369 104.7l.4 2.5 .5-2.5 .4 2.5 .5-2.5M369.3 119.4h.7M370.5 118.2h-1.2v2.5M372.3 118.2v2.5M372.9 105.1l-.5-.4a1.27 1.27 0 0 0-1 1.2 1.27 1.27 0 0 0 1 1.3l.5-.4v-.9h-.6M374 118.2v2.5h1.2M374.2 114.6l.3-.2a1.27 1.27 0 0 1 1 1.3 1.27 1.27 0 0 1-1 1.2l-.3-.2a1.44 1.44 0 0 1 0-2.1zM374.5 104.7a1.94 1.94 0 0 1 0 2.5M376.4 119.4h.8M377.6 114.9l-.4-.5a1.27 1.27 0 0 0-1.1 1.3 1.27 1.27 0 0 0 1.1 1.2l.4-.4v-.8h-.6M377.6 118.2h-1.2v2.5h1.2M378.8 115.7l1-.2v-.9l-1-.2v2.5"/>
<path d="M379.5 115.7l.5 1.2M381 116.9l.8-2.5 .7 2.5M381.3 116.1h.9M382.4 118.2v2.5l-1.2-2.5v2.5M382.9 117.8l.7-.2 .2 .6-.6 .2zM383.4 116.9v-2.5l.7 2.1 .8-2.1v2.5M387.6 119.4h.7M388.4 114.6l.3-.2a1.27 1.27 0 0 1 1.1 1.3 1.27 1.27 0 0 1-1.1 1.2l-.3-.2a1.44 1.44 0 0 1 0-2.1zM388.8 118.2h-1.2v2.5h1.2M390.7 115.7h.7M391 118.6l-.4-.4-.3 .2a1.58 1.58 0 0 0 .3 2.3 .78 .78 0 0 0 .5-.7 .78 .78 0 0 0-.5-.8l-.5 .2-.1 .5M391.9 114.4h-1.2v2.5"/>
<path d="M392.6 118.4l.3-.2 .3 .2a1.58 1.58 0 0 1-.3 2.3l-.3-.2a1.73 1.73 0 0 1 0-2.1zM395.7 118.6l-.4-.4-.3 .2a1.58 1.58 0 0 0 .3 2.3 .78 .78 0 0 0 .5-.7 .78 .78 0 0 0-.5-.8l-.4 .2-.2 .5M397.1 118.2h1.2l-.6 2.5M399.5 118.2h1.1l-.5 2.5M328.8 120.7l.7-2.5 .8 2.5M338.3 120.7l.7-2.5 .8 2.5M348.5 135.7l-.1-.2 .1 .2-.3 .4M350.4 133.4l.3-.2a.62 .62 0 0 1 .8 .6l-.5 .4a.7 .7 0 0 1 .5 1.1 .7 .7 0 0 1-1.2 0M350.7 134.2h.3M352.4 134.4l.3-.4h.3l.3 .4v1.3M352.4 134v1.7M353.3 134.4l.3-.4h.3l.3 .4v1.3"/>
<path d="M354.7 134.4l.3-.4h.3l.3 .4v1.3M354.7 134v1.7M355.6 134.4l.3-.4h.3l.3 .4v1.3M357.9 135.5l.1 .2zM365 120.5l.1 .2zM383.5 130.7h.8M384.7 129.4h-1.2v2.5h1.2M385.8 128.2l.7-2.5 .8 2.5M385.9 130.7l1.1-.2v-.9l-1.1-.2v2.5M386.1 127.4h.9M386.7 130.7l.4 1.2M388.3 125.7v2.5h1.2"/>
<path d="M390.8 129.6l.3-.2a1.27 1.27 0 0 1 1.1 1.3 1.27 1.27 0 0 1-1.1 1.2l-.3-.2a1.44 1.44 0 0 1 0-2.1zM392.9 125.7h1l.2 .2-.2 .8 .3 .4v.7l-.3 .4h-1zM392.9 126.7h1M393 130.7h.8M394.2 129.4h-1.2v2.5M395.4 125.7v2.5h1.2M397.6 129.4h1.5M397.9 125.9l.3-.2a1.27 1.27 0 0 1 1.1 1.2 1.27 1.27 0 0 1-1.1 1.3l-.3-.2a1.44 1.44 0 0 1 0-2.1zM398.4 129.4v2.5M400.2 130.7h1.2M400.2 129.4v2.5M401.4 126.1l-.5-.4a1.27 1.27 0 0 0-1 1.2 1.27 1.27 0 0 0 1 1.3l.5-.4"/>
<path d="M401.4 129.4v2.5M402.3 120.5l.1 .2zM402.5 125.7v2.5M402.5 130.7h.8M403.1 126.5l.6 1.7M403.7 129.4h-1.2v2.5h1.2M403.7 125.7l-1.2 1.4M406.1 126.1l-.4-.4a.62 .62 0 0 0-.8 .6l.5 .4a.73 .73 0 0 1 .7 .8 .73 .73 0 0 1-.7 .7l-.6-.6M116.2 152.1h-6l-9 9.5M147.5 152.1h1.2l.5-.3 .2-.3v-.7l-.2-.3-.5-.4h-1.2v4M148.7 152.1l.7 2M151.3 150.1l1 2v2"/>
<path d="M153.2 150.1l-.9 2M339.3 149.2l-.4-.2-.2 .4 .6 .5 .2 .4-.3 .4h-.3l-.3-.4M343 143.2l.8-2.5 .7 2.5M343 150.7v-2.5l.8 2.1 .7-2.1v2.5M343.3 142.4h.9M345.4 150.7l.7-2.5 .8 2.5M345.7 149.9h.9M346.7 140.7v2.5l-1.2-2.5v2.5M347.9 148.2l1.2 2.5M349.1 141.1l-.4-.4a1.27 1.27 0 0 0-1.1 1.2 1.27 1.27 0 0 0 1.1 1.3l.4-.4M349.1 148.2l-1.2 2.5M350.3 141.9h.7"/>
<path d="M351.5 140.7h-1.2v2.5h1.2M353.1 143l.2 .2zM337.7 171.6l.4-.2 .4 .2a1.84 1.84 0 0 1-.4 2.8l-.4-.3a2 2 0 0 1 0-2.5zM338.7 177.9l-.6-.5-.4 .2a1.84 1.84 0 0 0 .4 2.8 1.07 1.07 0 0 0 .6-1.5l-.6-.3-.5 .3-.2 .5M339.1 167.6h-1.7l1.3-2.2v3M356.1 165.4v3M356.1 171.4v3M356.1 177.4v3M358.4 165.9l.5-.5h.4l.6 .5a1.16 1.16 0 0 1-1 1.2l-.5 1.3h1.5M358.7 177.6l.4-.2 .4 .2a1.84 1.84 0 0 1-.4 2.8l-.4-.3a2 2 0 0 1 0-2.5zM359.1 171.4v3M403.6 178.9h1.1"/>
<path d="M403.6 172.9h1.1M403.6 166.9h1.1M406.4 165.9l.5-.5h.4l.6 .5a1.16 1.16 0 0 1-1 1.2l-.5 1.3h1.5M406.7 177.6l.4-.2 .4 .2a1.84 1.84 0 0 1-.4 2.8l-.4-.3a2 2 0 0 1 0-2.5zM407.1 171.4v3M337.4 183.9l.5-.5h.4l.6 .5a1.16 1.16 0 0 1-1 1.2l-.5 1.3h1.5M337.9 190.6l-.5-.5a.77 .77 0 0 1 .9-.7l.6 .5-.2 .5-.4 .2M339.1 197.6h-1.7l1.3-2.2v3M358.4 195.4h1.5l-.8 3M358.9 190.6l-.5-.5a.77 .77 0 0 1 .9-.7l.6 .5v.2l-.6 .5M359.9 184.4l-.2 .5-.6 .2-.5-.2a1.07 1.07 0 0 1 .5-1.5l.4 .2a1.84 1.84 0 0 1-.4 2.8l-.5-.5M403.6 196.9h1.1"/>
<path d="M403.6 190.9h1.1M403.6 184.9h1.1M406.4 195.4h1.5l-.8 3M406.9 190.6l-.5-.5a.77 .77 0 0 1 .9-.7l.6 .5v.2l-.6 .5M407.9 184.4l-.2 .5-.6 .2-.5-.2a1.07 1.07 0 0 1 .5-1.5l.4 .2a1.84 1.84 0 0 1-.4 2.8l-.5-.5M337.4 213.9l.5-.5h.4l.6 .5a1.16 1.16 0 0 1-1 1.2l-.5 1.3h1.5M337.7 201.6l.4-.2 .4 .2a1.84 1.84 0 0 1-.4 2.8l-.4-.3a2 2 0 0 1 0-2.5zM338.7 207.9l-.6-.5-.4 .2a1.84 1.84 0 0 0 .4 2.8 1.07 1.07 0 0 0 .6-1.5l-.6-.3-.5 .3-.2 .5M358.6 219.6l.3-.2a.77 .77 0 0 1 1 .7l-.6 .5a.86 .86 0 0 1 .5 1.4 .86 .86 0 0 1-1.4-.1M359.7 201.9l-.6-.5-.4 .2a1.84 1.84 0 0 0 .4 2.8 1.07 1.07 0 0 0 .6-1.5l-.6-.3-.5 .3-.2 .5M359.9 207.4h-1.2l-.1 1.2a.93 .93 0 0 1 1.3 .2 .93 .93 0 0 1-.2 1.3 .93 .93 0 0 1-1.3-.2M360.1 215.6h-1.7l1.3-2.2v3"/>
<path d="M403.6 214.9h1.1M403.6 208.9h1.1M403.6 202.9h1.1M406.6 219.6l.3-.2a.77 .77 0 0 1 1 .7l-.6 .5a.86 .86 0 0 1 .5 1.4 .86 .86 0 0 1-1.4-.1M407.7 201.9l-.6-.5-.4 .2a1.84 1.84 0 0 0 .4 2.8 1.07 1.07 0 0 0 .6-1.5l-.6-.3-.5 .3-.2 .5M407.9 207.4h-1.2l-.1 1.2a.93 .93 0 0 1 1.3 .2 .93 .93 0 0 1-.2 1.3 .93 .93 0 0 1-1.3-.2M408.1 215.6h-1.7l1.3-2.2v3M42.4 235h1.2l.5-.3 .2-.4v-.6l-.2-.4-.5-.3h-1.2v4M43.6 235l.7 2M46.2 235h1.2M48.1 233h-1.9v4h1.9M137.4 233v3.3l.7 .7h.5l.7-.7v-3.3"/>
<path d="M141 233h2.3M142.1 233v4M337.9 220.6l-.5-.5a.77 .77 0 0 1 .9-.7l.6 .5-.2 .5-.4 .2M339.1 227.6h-1.7l1.3-2.2v3M345.6 231.4h.4v3h-.4zM346 231.4h.4l1.3 3h-.3zM347.7 231.4h.4v3h-.4zM348.9 230.6h.5l.2 .3v.5l-.2 .2h-.5l-.3-.2v-.5zM354 231.6a1.26 1.26 0 0 1 1.3-.3 1.26 1.26 0 0 1 .8 1.1h-.4a.91 .91 0 0 0-.8-.7 .91 .91 0 0 0-.9 .7v1a.91 .91 0 0 0 .9 .6 .91 .91 0 0 0 .8-.6h.4a1.27 1.27 0 0 1-1.2 1 1.27 1.27 0 0 1-1.3-1l.1-1.4zM355.7 232.4h.4v1h-.4zM356.6 231.4h.4v3h-.4zM357 231.4h1.9v.4h-1.9z"/>
<path d="M357 232.6h1.6v.4h-1.6zM358.4 225.9l.5-.5h.4l.6 .5a1.16 1.16 0 0 1-1 1.2l-.5 1.3h1.5M358.9 220.6h.4M362.4 231.4h.3v3h-.3zM362.7 231.4h1.2a.83 .83 0 0 1 .8 .8 .83 .83 0 0 1-.8 .8h-1.2v-.3h1.2l.3-.4-.3-.6h-1.2zM365.5 231.6a1.26 1.26 0 0 1 1.3-.3 1.26 1.26 0 0 1 .8 1.1h-.4a.91 .91 0 0 0-.8-.7 .91 .91 0 0 0-.9 .7v1a.91 .91 0 0 0 .9 .6 .91 .91 0 0 0 .8-.6h.4a1.27 1.27 0 0 1-1.2 1 1.27 1.27 0 0 1-1.3-1l.1-1.4zM367.2 232.4h.4v1h-.4zM368.5 231.5l.6-.1a.87 .87 0 0 1 1.1 .6l-1.3-.2-.2 .5 .4 .4v.3l-.4-.1-.5-.6zM369.1 232.7a1.01 1.01 0 0 1 1.3 1.2 1.27 1.27 0 0 1-2.3-.3h.5l.3 .4 1-.2v-.6l-.8-.2zM370.9 234.1h.3v.3h-.3zM402.5 231.4h1.9v.4h-1.9zM402.5 232.6h1.6v.4h-1.6z"/>
<path d="M402.5 234h1.9v.4h-1.9zM403.6 226.9h1.1M403.6 220.9h1.1M404.9 231.4h.3v3h-.3zM405.2 231.4h1.2a.83 .83 0 0 1 .8 .8 .83 .83 0 0 1-.8 .8h-1.2v-.3h1.2l.3-.4-.3-.6h-1.2zM406.2 232.8h.5l.5 1.6h-.4zM406.4 225.9l.5-.5h.4l.6 .5a1.16 1.16 0 0 1-1 1.2l-.5 1.3h1.5M406.9 220.6h.4M95.2 246.4l1.1 1-3.4 2.9zM104.3 243.9h-6l-5.4 6.4M108 240.9l-3.4 6M109.6 249.1h35.9v8h-35.9z"/>
<path d="M111.5 241.9v4M111.6 253.1h6M114.6 250.1v6M115.1 245.6l.2 .3h-.2zM119.1 241.9v4M121 249.1v8M126.6 250.1l-3.3 6M133.5 251.4l.5-.3 .5 .3a2.53 2.53 0 0 1-.5 3.7l-.5-.4a2.77 2.77 0 0 1 0-3.3zM137.5 254.7l.3 .4h-.3zM141.6 251.1v4"/>
<circle cx="88.1" cy="58.4" r=".75"/>
<circle cx="100.8" cy="72.7" r=".75"/>
<circle cx="365.1" cy="106.5" r=".7"/>
<circle cx="100.7" cy="162.2" r=".75"/>
<circle cx="338.1" cy="191.5" r=".86"/>
<circle cx="359.1" cy="191.5" r=".86"/>
<circle cx="407.1" cy="191.5" r=".86"/>
<circle cx="338.1" cy="221.5" r=".86"/>
<circle cx="106.3" cy="243.9" r="1.96"/>
<circle cx="114.6" cy="253" r="1.99"/>
<circle cx="124.9" cy="253.1" r="1.96"/>
</g>
<path d="M345.8 231.4v3M347.9 231.4v3M356.8 231.4v3M362.6 231.4v3M405.1 231.4v3" fill="none" stroke="#000" stroke-width=".37"/>
<!-- layer: SYMBOL -->
<path d="M29.9 212l4 6.9h-8zM198.9 276.8l4 6.9h-8zM238.4 276.8l4 6.9h-8z" fill="none" stroke="#000" stroke-width=".3"/>
<use href="#words"/>
</svg>
